VERSION 5.8 ;
BUSBITCHARS "[]" ;
DIVIDERCHAR "/" ;
UNITS
    DATABASE MICRONS 1000 ;
END UNITS

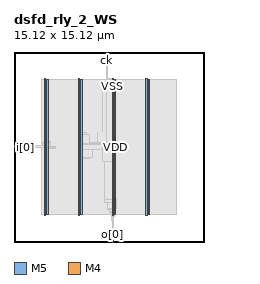
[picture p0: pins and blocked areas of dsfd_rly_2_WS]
MACRO dsfd_rly_2_WS
  FOREIGN dsfd_rly_2_WS 0 0 ;
  CLASS BLOCK ;
  SIZE 15.12 BY 15.12 ;
  PIN ck
    DIRECTION INPUT ;
    USE SIGNAL ;
    PORT
      LAYER M5 ;
        RECT  7.344 15.036 7.368 15.12 ;
    END
  END ck
  PIN i[0]
    DIRECTION INPUT ;
    USE SIGNAL ;
    PORT
      LAYER M4 ;
        RECT  0 7.536 0.084 7.56 ;
    END
  END i[0]
  PIN i[1]
    DIRECTION INPUT ;
    USE SIGNAL ;
    PORT
      LAYER M4 ;
        RECT  0 7.632 0.084 7.656 ;
    END
  END i[1]
  PIN o[0]
    DIRECTION OUTPUT ;
    USE SIGNAL ;
    PORT
      LAYER M5 ;
        RECT  7.824 0 7.848 0.084 ;
    END
  END o[0]
  PIN o[1]
    DIRECTION OUTPUT ;
    USE SIGNAL ;
    PORT
      LAYER M5 ;
        RECT  7.92 0 7.944 0.084 ;
    END
  END o[1]
  PIN rs
    DIRECTION INPUT ;
    USE SIGNAL ;
    PORT
      LAYER M5 ;
        RECT  7.44 15.036 7.464 15.12 ;
    END
  END rs
  PIN VDD
    DIRECTION INOUT ;
    USE POWER ;
    PORT
      LAYER M5 ;
        RECT  10.692 2.151 10.812 12.969 ;
        RECT  7.992 2.151 8.112 12.969 ;
        RECT  5.292 2.151 5.412 12.969 ;
        RECT  2.592 2.151 2.712 12.969 ;
    END
  END VDD
  PIN VSS
    DIRECTION INOUT ;
    USE GROUND ;
    PORT
      LAYER M5 ;
        RECT  10.5 2.137 10.62 12.983 ;
        RECT  7.8 2.137 7.92 12.983 ;
        RECT  5.1 2.137 5.22 12.983 ;
        RECT  2.4 2.137 2.52 12.983 ;
    END
  END VSS
  OBS
    LAYER RVTN ;
     RECT  2.16 2.16 12.96 2.295 ;
     RECT  2.16 2.565 12.96 2.835 ;
     RECT  2.16 3.105 12.96 3.375 ;
     RECT  2.16 3.645 12.96 3.915 ;
     RECT  2.16 4.185 12.96 4.455 ;
     RECT  2.16 4.725 12.96 4.995 ;
     RECT  2.16 5.265 12.96 5.535 ;
     RECT  2.16 5.805 12.96 6.075 ;
     RECT  2.16 6.345 12.96 6.615 ;
     RECT  2.16 6.885 12.96 7.155 ;
     RECT  2.16 7.425 12.96 7.695 ;
     RECT  2.16 7.965 12.96 8.235 ;
     RECT  2.16 8.505 12.96 8.775 ;
     RECT  2.16 9.045 12.96 9.315 ;
     RECT  2.16 9.585 12.96 9.855 ;
     RECT  2.16 10.125 12.96 10.395 ;
     RECT  2.16 10.665 12.96 10.935 ;
     RECT  2.16 11.205 12.96 11.475 ;
     RECT  2.16 11.745 12.96 12.015 ;
     RECT  2.16 12.285 12.96 12.555 ;
     RECT  2.16 12.825 12.96 12.96 ;
    LAYER RVTP ;
     RECT  2.16 2.295 12.96 2.565 ;
     RECT  2.16 2.835 12.96 3.105 ;
     RECT  2.16 3.375 12.96 3.645 ;
     RECT  2.16 3.915 12.96 4.185 ;
     RECT  2.16 4.455 12.96 4.725 ;
     RECT  2.16 4.995 12.96 5.265 ;
     RECT  2.16 5.535 12.96 5.805 ;
     RECT  2.16 6.075 12.96 6.345 ;
     RECT  2.16 6.615 12.96 6.885 ;
     RECT  2.16 7.155 12.96 7.425 ;
     RECT  2.16 7.695 12.96 7.965 ;
     RECT  2.16 8.235 12.96 8.505 ;
     RECT  2.16 8.775 12.96 9.045 ;
     RECT  2.16 9.315 12.96 9.585 ;
     RECT  2.16 9.855 12.96 10.125 ;
     RECT  2.16 10.395 12.96 10.665 ;
     RECT  2.16 10.935 12.96 11.205 ;
     RECT  2.16 11.475 12.96 11.745 ;
     RECT  2.16 12.015 12.96 12.285 ;
     RECT  2.16 12.555 12.96 12.825 ;
    LAYER M1 ;
     RECT  2.16 2.151 12.96 12.969 ;
    LAYER M2 ;
     RECT  2.16 2.151 12.96 12.969 ;
    LAYER M3 ;
     RECT  7.776 1.723 7.794 2.011 ;
     RECT  7.776 2.011 8.01 2.335 ;
     RECT  2.415 2.143 2.505 2.413 ;
     RECT  5.115 2.143 5.205 2.413 ;
     RECT  7.632 2.335 8.01 2.413 ;
     RECT  10.515 2.143 10.605 2.413 ;
     RECT  7.632 2.413 8.097 2.605 ;
     RECT  7.416 2.605 8.097 2.641 ;
     RECT  7.416 2.641 8.154 3.181 ;
     RECT  7.164 3.181 8.154 3.371 ;
     RECT  7.164 3.371 8.097 6.421 ;
     RECT  5.115 2.413 5.397 6.655 ;
     RECT  5.115 6.655 6.03 6.691 ;
     RECT  7.056 6.421 8.097 7.349 ;
     RECT  5.115 6.691 6.282 7.357 ;
     RECT  7.056 7.349 7.074 7.357 ;
     RECT  2.415 2.413 2.697 7.465 ;
     RECT  2.415 7.465 3.33 7.531 ;
     RECT  2.304 7.531 3.33 7.619 ;
     RECT  5.115 7.357 7.074 7.889 ;
     RECT  5.115 7.889 6.678 7.901 ;
     RECT  2.304 7.619 2.934 7.925 ;
     RECT  6.48 7.901 6.678 7.925 ;
     RECT  2.415 7.925 2.934 7.961 ;
     RECT  5.115 7.901 5.742 8.699 ;
     RECT  6.624 7.925 6.678 8.699 ;
     RECT  5.115 8.699 5.49 8.735 ;
     RECT  7.056 8.815 7.074 11.939 ;
     RECT  7.815 7.349 8.097 12.055 ;
     RECT  2.415 7.961 2.697 12.707 ;
     RECT  5.115 8.735 5.397 12.707 ;
     RECT  7.416 12.055 8.097 12.707 ;
     RECT  10.515 2.413 10.797 12.707 ;
     RECT  2.415 12.707 2.505 12.977 ;
     RECT  5.115 12.707 5.205 12.977 ;
     RECT  7.416 12.707 7.905 12.977 ;
     RECT  10.515 12.707 10.605 12.977 ;
     RECT  7.416 12.977 7.434 15.005 ;
    LAYER M4 ;
     RECT  0.06 7.536 2.408 7.656 ;
     RECT  2.408 2.148 2.512 12.972 ;
     RECT  2.512 2.418 2.704 12.702 ;
     RECT  5.108 2.148 5.212 12.972 ;
     RECT  5.212 2.418 5.404 12.702 ;
     RECT  5.404 7.776 6.035 8.568 ;
     RECT  6.035 7.776 6.076 7.896 ;
     RECT  7.405 14.976 7.489 15 ;
     RECT  7.765 1.728 7.808 1.752 ;
     RECT  6.076 7.776 7.808 7.8 ;
     RECT  7.808 1.728 7.859 12.972 ;
     RECT  7.859 2.016 7.912 12.972 ;
     RECT  7.912 2.016 8.021 12.702 ;
     RECT  8.021 2.418 8.104 12.702 ;
     RECT  10.508 2.148 10.612 12.972 ;
     RECT  10.612 2.418 10.804 12.702 ;
    LAYER M5 ;
     RECT  7.824 0.016 7.944 2.137 ;
     RECT  2.4 2.137 2.52 2.151 ;
     RECT  5.1 2.137 5.22 2.151 ;
     RECT  7.8 2.137 7.944 2.151 ;
     RECT  10.5 2.137 10.62 2.151 ;
     RECT  7.8 2.151 8.112 7.765 ;
     RECT  5.1 2.151 5.412 7.861 ;
     RECT  5.1 7.861 6.024 8.579 ;
     RECT  2.4 2.151 2.712 12.969 ;
     RECT  5.1 8.579 5.412 12.969 ;
     RECT  7.344 7.765 8.112 12.969 ;
     RECT  10.5 2.151 10.812 12.969 ;
     RECT  2.4 12.969 2.52 12.983 ;
     RECT  5.1 12.969 5.22 12.983 ;
     RECT  7.344 12.969 7.92 12.983 ;
     RECT  10.5 12.969 10.62 12.983 ;
     RECT  7.344 12.983 7.368 14.965 ;
     RECT  7.344 14.965 7.464 15.056 ;
  END
END dsfd_rly_2_WS
END LIBRARY
